VERSION 5.7 ;
BUSBITCHARS "[]" ;
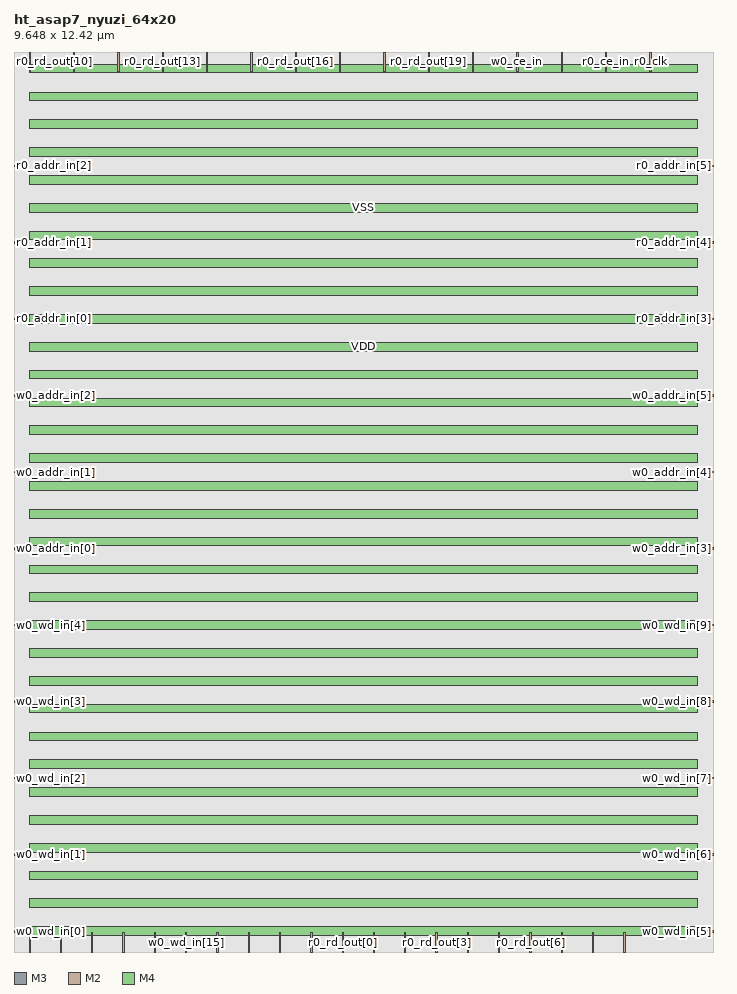
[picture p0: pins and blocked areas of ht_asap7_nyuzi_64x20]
MACRO ht_asap7_nyuzi_64x20
  FOREIGN ht_asap7_nyuzi_64x20 0 0 ;
  SYMMETRY X Y R90 ;
  SIZE 9.648 BY 12.420 ;
  CLASS BLOCK ;
  PIN w0_wd_in[0]
    DIRECTION INPUT ;
    USE SIGNAL ;
    SHAPE ABUTMENT ;
    PORT
      LAYER M3 ;
      RECT 0.000 0.276 0.072 0.300 ;
    END
  END w0_wd_in[0]
  PIN w0_wd_in[1]
    DIRECTION INPUT ;
    USE SIGNAL ;
    SHAPE ABUTMENT ;
    PORT
      LAYER M3 ;
      RECT 0.000 1.332 0.072 1.356 ;
    END
  END w0_wd_in[1]
  PIN w0_wd_in[2]
    DIRECTION INPUT ;
    USE SIGNAL ;
    SHAPE ABUTMENT ;
    PORT
      LAYER M3 ;
      RECT 0.000 2.388 0.072 2.412 ;
    END
  END w0_wd_in[2]
  PIN w0_wd_in[3]
    DIRECTION INPUT ;
    USE SIGNAL ;
    SHAPE ABUTMENT ;
    PORT
      LAYER M3 ;
      RECT 0.000 3.444 0.072 3.468 ;
    END
  END w0_wd_in[3]
  PIN w0_wd_in[4]
    DIRECTION INPUT ;
    USE SIGNAL ;
    SHAPE ABUTMENT ;
    PORT
      LAYER M3 ;
      RECT 0.000 4.500 0.072 4.524 ;
    END
  END w0_wd_in[4]
  PIN w0_wd_in[5]
    DIRECTION INPUT ;
    USE SIGNAL ;
    SHAPE ABUTMENT ;
    PORT
      LAYER M3 ;
      RECT 9.576 0.276 9.648 0.300 ;
    END
  END w0_wd_in[5]
  PIN w0_wd_in[6]
    DIRECTION INPUT ;
    USE SIGNAL ;
    SHAPE ABUTMENT ;
    PORT
      LAYER M3 ;
      RECT 9.576 1.332 9.648 1.356 ;
    END
  END w0_wd_in[6]
  PIN w0_wd_in[7]
    DIRECTION INPUT ;
    USE SIGNAL ;
    SHAPE ABUTMENT ;
    PORT
      LAYER M3 ;
      RECT 9.576 2.388 9.648 2.412 ;
    END
  END w0_wd_in[7]
  PIN w0_wd_in[8]
    DIRECTION INPUT ;
    USE SIGNAL ;
    SHAPE ABUTMENT ;
    PORT
      LAYER M3 ;
      RECT 9.576 3.444 9.648 3.468 ;
    END
  END w0_wd_in[8]
  PIN w0_wd_in[9]
    DIRECTION INPUT ;
    USE SIGNAL ;
    SHAPE ABUTMENT ;
    PORT
      LAYER M3 ;
      RECT 9.576 4.500 9.648 4.524 ;
    END
  END w0_wd_in[9]
  PIN w0_wd_in[10]
    DIRECTION INPUT ;
    USE SIGNAL ;
    SHAPE ABUTMENT ;
    PORT
      LAYER M2 ;
      RECT 0.207 0.000 0.225 0.270 ;
    END
  END w0_wd_in[10]
  PIN w0_wd_in[11]
    DIRECTION INPUT ;
    USE SIGNAL ;
    SHAPE ABUTMENT ;
    PORT
      LAYER M2 ;
      RECT 0.639 0.000 0.657 0.270 ;
    END
  END w0_wd_in[11]
  PIN w0_wd_in[12]
    DIRECTION INPUT ;
    USE SIGNAL ;
    SHAPE ABUTMENT ;
    PORT
      LAYER M2 ;
      RECT 1.071 0.000 1.089 0.270 ;
    END
  END w0_wd_in[12]
  PIN w0_wd_in[13]
    DIRECTION INPUT ;
    USE SIGNAL ;
    SHAPE ABUTMENT ;
    PORT
      LAYER M2 ;
      RECT 1.503 0.000 1.521 0.270 ;
    END
  END w0_wd_in[13]
  PIN w0_wd_in[14]
    DIRECTION INPUT ;
    USE SIGNAL ;
    SHAPE ABUTMENT ;
    PORT
      LAYER M2 ;
      RECT 1.935 0.000 1.953 0.270 ;
    END
  END w0_wd_in[14]
  PIN w0_wd_in[15]
    DIRECTION INPUT ;
    USE SIGNAL ;
    SHAPE ABUTMENT ;
    PORT
      LAYER M2 ;
      RECT 2.367 0.000 2.385 0.270 ;
    END
  END w0_wd_in[15]
  PIN w0_wd_in[16]
    DIRECTION INPUT ;
    USE SIGNAL ;
    SHAPE ABUTMENT ;
    PORT
      LAYER M2 ;
      RECT 2.799 0.000 2.817 0.270 ;
    END
  END w0_wd_in[16]
  PIN w0_wd_in[17]
    DIRECTION INPUT ;
    USE SIGNAL ;
    SHAPE ABUTMENT ;
    PORT
      LAYER M2 ;
      RECT 3.231 0.000 3.249 0.270 ;
    END
  END w0_wd_in[17]
  PIN w0_wd_in[18]
    DIRECTION INPUT ;
    USE SIGNAL ;
    SHAPE ABUTMENT ;
    PORT
      LAYER M2 ;
      RECT 3.663 0.000 3.681 0.270 ;
    END
  END w0_wd_in[18]
  PIN w0_wd_in[19]
    DIRECTION INPUT ;
    USE SIGNAL ;
    SHAPE ABUTMENT ;
    PORT
      LAYER M2 ;
      RECT 4.095 0.000 4.113 0.270 ;
    END
  END w0_wd_in[19]
  PIN r0_rd_out[0]
    DIRECTION OUTPUT ;
    USE SIGNAL ;
    SHAPE ABUTMENT ;
    PORT
      LAYER M2 ;
      RECT 4.527 0.000 4.545 0.270 ;
    END
  END r0_rd_out[0]
  PIN r0_rd_out[1]
    DIRECTION OUTPUT ;
    USE SIGNAL ;
    SHAPE ABUTMENT ;
    PORT
      LAYER M2 ;
      RECT 4.959 0.000 4.977 0.270 ;
    END
  END r0_rd_out[1]
  PIN r0_rd_out[2]
    DIRECTION OUTPUT ;
    USE SIGNAL ;
    SHAPE ABUTMENT ;
    PORT
      LAYER M2 ;
      RECT 5.391 0.000 5.409 0.270 ;
    END
  END r0_rd_out[2]
  PIN r0_rd_out[3]
    DIRECTION OUTPUT ;
    USE SIGNAL ;
    SHAPE ABUTMENT ;
    PORT
      LAYER M2 ;
      RECT 5.823 0.000 5.841 0.270 ;
    END
  END r0_rd_out[3]
  PIN r0_rd_out[4]
    DIRECTION OUTPUT ;
    USE SIGNAL ;
    SHAPE ABUTMENT ;
    PORT
      LAYER M2 ;
      RECT 6.255 0.000 6.273 0.270 ;
    END
  END r0_rd_out[4]
  PIN r0_rd_out[5]
    DIRECTION OUTPUT ;
    USE SIGNAL ;
    SHAPE ABUTMENT ;
    PORT
      LAYER M2 ;
      RECT 6.687 0.000 6.705 0.270 ;
    END
  END r0_rd_out[5]
  PIN r0_rd_out[6]
    DIRECTION OUTPUT ;
    USE SIGNAL ;
    SHAPE ABUTMENT ;
    PORT
      LAYER M2 ;
      RECT 7.119 0.000 7.137 0.270 ;
    END
  END r0_rd_out[6]
  PIN r0_rd_out[7]
    DIRECTION OUTPUT ;
    USE SIGNAL ;
    SHAPE ABUTMENT ;
    PORT
      LAYER M2 ;
      RECT 7.551 0.000 7.569 0.270 ;
    END
  END r0_rd_out[7]
  PIN r0_rd_out[8]
    DIRECTION OUTPUT ;
    USE SIGNAL ;
    SHAPE ABUTMENT ;
    PORT
      LAYER M2 ;
      RECT 7.983 0.000 8.001 0.270 ;
    END
  END r0_rd_out[8]
  PIN r0_rd_out[9]
    DIRECTION OUTPUT ;
    USE SIGNAL ;
    SHAPE ABUTMENT ;
    PORT
      LAYER M2 ;
      RECT 8.415 0.000 8.433 0.270 ;
    END
  END r0_rd_out[9]
  PIN r0_rd_out[10]
    DIRECTION OUTPUT ;
    USE SIGNAL ;
    SHAPE ABUTMENT ;
    PORT
      LAYER M2 ;
      RECT 0.207 12.150 0.225 12.420 ;
    END
  END r0_rd_out[10]
  PIN r0_rd_out[11]
    DIRECTION OUTPUT ;
    USE SIGNAL ;
    SHAPE ABUTMENT ;
    PORT
      LAYER M2 ;
      RECT 0.819 12.150 0.837 12.420 ;
    END
  END r0_rd_out[11]
  PIN r0_rd_out[12]
    DIRECTION OUTPUT ;
    USE SIGNAL ;
    SHAPE ABUTMENT ;
    PORT
      LAYER M2 ;
      RECT 1.431 12.150 1.449 12.420 ;
    END
  END r0_rd_out[12]
  PIN r0_rd_out[13]
    DIRECTION OUTPUT ;
    USE SIGNAL ;
    SHAPE ABUTMENT ;
    PORT
      LAYER M2 ;
      RECT 2.043 12.150 2.061 12.420 ;
    END
  END r0_rd_out[13]
  PIN r0_rd_out[14]
    DIRECTION OUTPUT ;
    USE SIGNAL ;
    SHAPE ABUTMENT ;
    PORT
      LAYER M2 ;
      RECT 2.655 12.150 2.673 12.420 ;
    END
  END r0_rd_out[14]
  PIN r0_rd_out[15]
    DIRECTION OUTPUT ;
    USE SIGNAL ;
    SHAPE ABUTMENT ;
    PORT
      LAYER M2 ;
      RECT 3.267 12.150 3.285 12.420 ;
    END
  END r0_rd_out[15]
  PIN r0_rd_out[16]
    DIRECTION OUTPUT ;
    USE SIGNAL ;
    SHAPE ABUTMENT ;
    PORT
      LAYER M2 ;
      RECT 3.879 12.150 3.897 12.420 ;
    END
  END r0_rd_out[16]
  PIN r0_rd_out[17]
    DIRECTION OUTPUT ;
    USE SIGNAL ;
    SHAPE ABUTMENT ;
    PORT
      LAYER M2 ;
      RECT 4.491 12.150 4.509 12.420 ;
    END
  END r0_rd_out[17]
  PIN r0_rd_out[18]
    DIRECTION OUTPUT ;
    USE SIGNAL ;
    SHAPE ABUTMENT ;
    PORT
      LAYER M2 ;
      RECT 5.103 12.150 5.121 12.420 ;
    END
  END r0_rd_out[18]
  PIN r0_rd_out[19]
    DIRECTION OUTPUT ;
    USE SIGNAL ;
    SHAPE ABUTMENT ;
    PORT
      LAYER M2 ;
      RECT 5.715 12.150 5.733 12.420 ;
    END
  END r0_rd_out[19]
  PIN w0_addr_in[0]
    DIRECTION INPUT ;
    USE SIGNAL ;
    SHAPE ABUTMENT ;
    PORT
      LAYER M3 ;
      RECT 0.000 5.556 0.072 5.580 ;
    END
  END w0_addr_in[0]
  PIN w0_addr_in[1]
    DIRECTION INPUT ;
    USE SIGNAL ;
    SHAPE ABUTMENT ;
    PORT
      LAYER M3 ;
      RECT 0.000 6.612 0.072 6.636 ;
    END
  END w0_addr_in[1]
  PIN w0_addr_in[2]
    DIRECTION INPUT ;
    USE SIGNAL ;
    SHAPE ABUTMENT ;
    PORT
      LAYER M3 ;
      RECT 0.000 7.668 0.072 7.692 ;
    END
  END w0_addr_in[2]
  PIN w0_addr_in[3]
    DIRECTION INPUT ;
    USE SIGNAL ;
    SHAPE ABUTMENT ;
    PORT
      LAYER M3 ;
      RECT 9.576 5.556 9.648 5.580 ;
    END
  END w0_addr_in[3]
  PIN w0_addr_in[4]
    DIRECTION INPUT ;
    USE SIGNAL ;
    SHAPE ABUTMENT ;
    PORT
      LAYER M3 ;
      RECT 9.576 6.612 9.648 6.636 ;
    END
  END w0_addr_in[4]
  PIN w0_addr_in[5]
    DIRECTION INPUT ;
    USE SIGNAL ;
    SHAPE ABUTMENT ;
    PORT
      LAYER M3 ;
      RECT 9.576 7.668 9.648 7.692 ;
    END
  END w0_addr_in[5]
  PIN r0_addr_in[0]
    DIRECTION INPUT ;
    USE SIGNAL ;
    SHAPE ABUTMENT ;
    PORT
      LAYER M3 ;
      RECT 0.000 8.724 0.072 8.748 ;
    END
  END r0_addr_in[0]
  PIN r0_addr_in[1]
    DIRECTION INPUT ;
    USE SIGNAL ;
    SHAPE ABUTMENT ;
    PORT
      LAYER M3 ;
      RECT 0.000 9.780 0.072 9.804 ;
    END
  END r0_addr_in[1]
  PIN r0_addr_in[2]
    DIRECTION INPUT ;
    USE SIGNAL ;
    SHAPE ABUTMENT ;
    PORT
      LAYER M3 ;
      RECT 0.000 10.836 0.072 10.860 ;
    END
  END r0_addr_in[2]
  PIN r0_addr_in[3]
    DIRECTION INPUT ;
    USE SIGNAL ;
    SHAPE ABUTMENT ;
    PORT
      LAYER M3 ;
      RECT 9.576 8.724 9.648 8.748 ;
    END
  END r0_addr_in[3]
  PIN r0_addr_in[4]
    DIRECTION INPUT ;
    USE SIGNAL ;
    SHAPE ABUTMENT ;
    PORT
      LAYER M3 ;
      RECT 9.576 9.780 9.648 9.804 ;
    END
  END r0_addr_in[4]
  PIN r0_addr_in[5]
    DIRECTION INPUT ;
    USE SIGNAL ;
    SHAPE ABUTMENT ;
    PORT
      LAYER M3 ;
      RECT 9.576 10.836 9.648 10.860 ;
    END
  END r0_addr_in[5]
  PIN w0_we_in
    DIRECTION INPUT ;
    USE SIGNAL ;
    SHAPE ABUTMENT ;
    PORT
      LAYER M2 ;
      RECT 6.327 12.150 6.345 12.420 ;
    END
  END w0_we_in
  PIN w0_ce_in
    DIRECTION INPUT ;
    USE SIGNAL ;
    SHAPE ABUTMENT ;
    PORT
      LAYER M2 ;
      RECT 6.939 12.150 6.957 12.420 ;
    END
  END w0_ce_in
  PIN w0_clk
    DIRECTION INPUT ;
    USE SIGNAL ;
    SHAPE ABUTMENT ;
    PORT
      LAYER M2 ;
      RECT 7.551 12.150 7.569 12.420 ;
    END
  END w0_clk
  PIN r0_ce_in
    DIRECTION INPUT ;
    USE SIGNAL ;
    SHAPE ABUTMENT ;
    PORT
      LAYER M2 ;
      RECT 8.163 12.150 8.181 12.420 ;
    END
  END r0_ce_in
  PIN r0_clk
    DIRECTION INPUT ;
    USE SIGNAL ;
    SHAPE ABUTMENT ;
    PORT
      LAYER M2 ;
      RECT 8.775 12.150 8.793 12.420 ;
    END
  END r0_clk
  PIN VSS
    DIRECTION INOUT ;
    USE GROUND ;
    PORT
      LAYER M4 ;
      RECT 0.216 0.228 9.432 0.348 ;
      RECT 0.216 0.996 9.432 1.116 ;
      RECT 0.216 1.764 9.432 1.884 ;
      RECT 0.216 2.532 9.432 2.652 ;
      RECT 0.216 3.300 9.432 3.420 ;
      RECT 0.216 4.068 9.432 4.188 ;
      RECT 0.216 4.836 9.432 4.956 ;
      RECT 0.216 5.604 9.432 5.724 ;
      RECT 0.216 6.372 9.432 6.492 ;
      RECT 0.216 7.140 9.432 7.260 ;
      RECT 0.216 7.908 9.432 8.028 ;
      RECT 0.216 8.676 9.432 8.796 ;
      RECT 0.216 9.444 9.432 9.564 ;
      RECT 0.216 10.212 9.432 10.332 ;
      RECT 0.216 10.980 9.432 11.100 ;
      RECT 0.216 11.748 9.432 11.868 ;
    END
  END VSS
  PIN VDD
    DIRECTION INOUT ;
    USE POWER ;
    PORT
      LAYER M4 ;
      RECT 0.216 0.612 9.432 0.732 ;
      RECT 0.216 1.380 9.432 1.500 ;
      RECT 0.216 2.148 9.432 2.268 ;
      RECT 0.216 2.916 9.432 3.036 ;
      RECT 0.216 3.684 9.432 3.804 ;
      RECT 0.216 4.452 9.432 4.572 ;
      RECT 0.216 5.220 9.432 5.340 ;
      RECT 0.216 5.988 9.432 6.108 ;
      RECT 0.216 6.756 9.432 6.876 ;
      RECT 0.216 7.524 9.432 7.644 ;
      RECT 0.216 8.292 9.432 8.412 ;
      RECT 0.216 9.060 9.432 9.180 ;
      RECT 0.216 9.828 9.432 9.948 ;
      RECT 0.216 10.596 9.432 10.716 ;
      RECT 0.216 11.364 9.432 11.484 ;
      RECT 0.216 12.132 9.432 12.252 ;
    END
  END VDD
  OBS
    LAYER M1 ;
    RECT 0 0 9.648 12.420 ;
    LAYER M2 ;
    RECT 0 0 9.648 12.420 ;
    LAYER M3 ;
    RECT 0 0 9.648 12.420 ;
    LAYER M4 ;
    RECT 0 0 9.648 12.420 ;
  END
END ht_asap7_nyuzi_64x20

END LIBRARY
